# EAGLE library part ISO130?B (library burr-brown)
Isolation Amplifier Precision, Lowest Cost

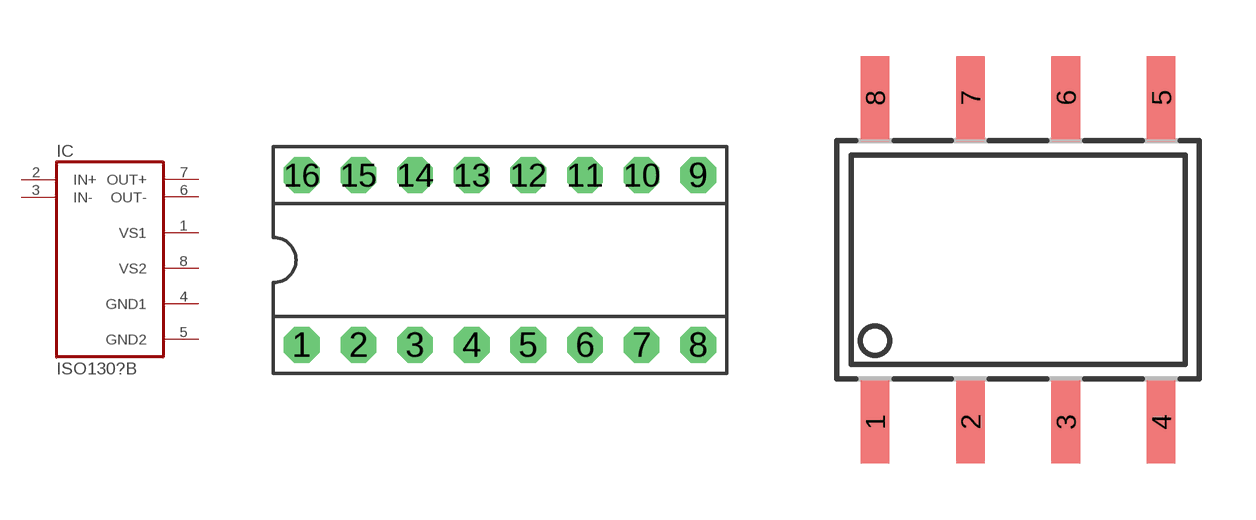
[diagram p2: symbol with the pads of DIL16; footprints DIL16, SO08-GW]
Designator prefix IC

## ISO130PB  [DIL16]
1  VS1  pwr
2  IN+  in
3  IN-  in
4  GND1  pwr
5  GND2  pwr
6  OUT-  out
7  OUT+  out
8  VS2  pwr

## ISO130UB  [SO08-GW]
Pads as for DIL16

## Footprint DIL16 (pad centres in mm)
Dual In Line
drill 0.813 pad 1.6 octagon: 1 -8.89,-3.81; 2 -6.35,-3.81; 3 -3.81,-3.81; 4 -1.27,-3.81; 5 1.27,-3.81; 6 3.81,-3.81; 7 6.35,-3.81; 8 8.89,-3.81; 9 8.89,3.81; 10 6.35,3.81; 11 3.81,3.81; 12 1.27,3.81; 13 -1.27,3.81; 14 -3.81,3.81; 15 -6.35,3.81; 16 -8.89,3.81

## Footprint SO08-GW (pad centres in mm)
Small Outline Package, gull wing
smd 0.762 x 2.21: 1 -3.81,-4.318; 2 -1.27,-4.318; 3 1.27,-4.318; 4 3.81,-4.318; 5 3.81,4.318; 6 1.27,4.318; 7 -1.27,4.318; 8 -3.81,4.318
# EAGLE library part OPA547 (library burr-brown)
Operational Amplifier High-Voltage, High-Current

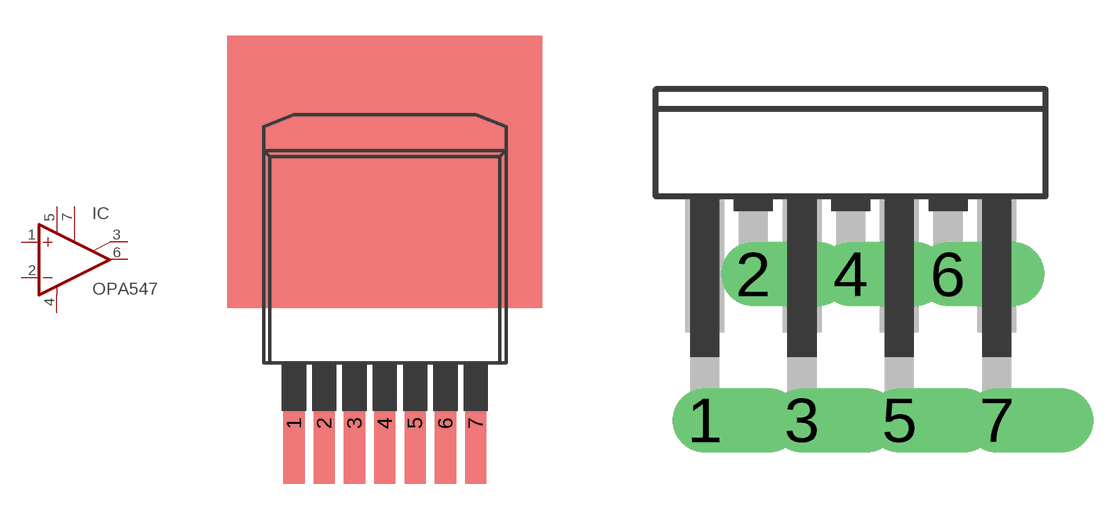
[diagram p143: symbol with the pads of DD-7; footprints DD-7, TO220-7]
Designator prefix IC

## OPA547F  [DD-7]
1  +IN  in
2  -IN  in
3  ILIM  in
4  V-  pwr
5  V+  pwr
6  OUT  out
7  E/S

## OPA547T  [TO220-7]
Pads as for DD-7

## Footprint DD-7 (pad centres in mm)
DPAC
smd 0.889 x 5.08: 1 -3.81,-6.985; 2 -2.54,-6.985; 3 -1.27,-6.985; 4 0,-6.985; 5 1.27,-6.985; 6 2.54,-6.985; 7 3.81,-6.985

## Footprint TO220-7 (pad centres in mm)
Molded Package
drill 1.118 pad 1.626 offset: 1 -3.81,-8.636; 2 -2.54,-4.826; 3 -1.27,-8.636; 4 0,-4.826; 5 1.27,-8.636; 6 2.54,-4.826; 7 3.81,-8.636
